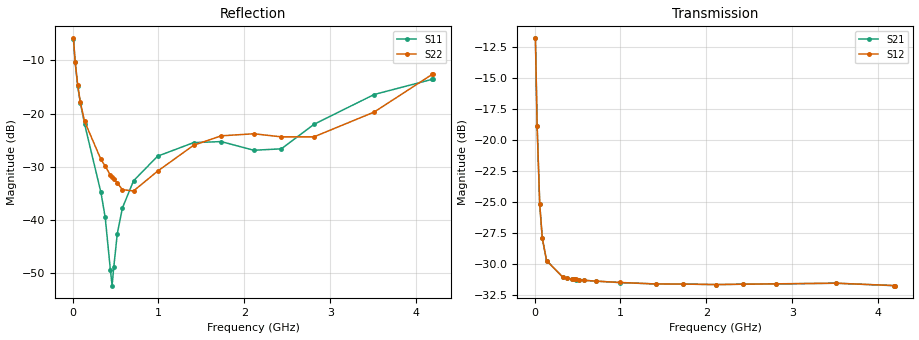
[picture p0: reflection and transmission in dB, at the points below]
! Integrated Device Technology
! Corporate Headquarters
! 6024 Silver Creek Valley Road
! San Jose, CA 95138  USA
! Phone:  1-408-284-8200
! Toll Free:  1-800-223-1366
! Webpage:  http://www.idt.com/
! Timing and RF Division
! 515 Groton Road, Suite 102
! Westford, MA 01886-6024
! Device:  F1950
! Description: 7-bit 0.25 dB Digital Step Attenuator
! Frequency:  150.0 -  4000.00 MHz
! Package:  4x4 mm Thin QFN Plastic Package: 24 pin
! Ports:  2 RF, 12 DC
!  Pin  1  = D0
!  Pin  2  = VDD
!  Pin  3  = Vmode
!  Pin  4  = GND
!  Pin  5  = RF1  =  Port 1
!  Pin  6  = GND
!  Pin  7  = GND
!  Pin  8  = GND
!  Pin  9  = GND
!  Pin 10  = GND
!  Pin 11  = GND
!  Pin 12  = GND
!  Pin 13  = GND
!  Pin 14  = RF2  =  Port 2
!  Pin 15  = GND
!  Pin 16  = LE
!  Pin 17  = CLK
!  Pin 18  = DATE
!  Pin 19  = D6
!  Pin 20  = D5
!  Pin 21  = D4
!  Pin 22  = D3
!  Pin 23  = D2
!  Pin 24  = D1
! State:  122
! Atten State:  30.50 dB
! Voltage:  +5.00 Volts
! Current:  Not Measured mA
! Data:  The device was measured on a the F195X evaluation board which has
!  individual transmission lines to the RF pins.  Data was collected
!  using a calibrated network analyzer.  The evaluation board was
!  de-embedded using a TRL calibration technique.
!  The reference plane is the edge of the package pin.
! Misc:  Board 2019
!  Action Tracker AT0250
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# GHz S dB R 50
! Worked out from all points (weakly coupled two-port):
!   420 points, 10 MHz to 4.2 GHz, reference 50 ohm
!   highest |S21| = -11.82 dB at 10 MHz (marker M1); lowest = -31.7 dB at 4.19 GHz (marker M2)
!   lowest |S11| = -52.3 dB at 460 MHz (marker M3), VSWR 1.00, Z = 49.8 - j0.0964 ohm
!   |S11| at or under -10 dB: 28.27 MHz to end of sweep
!   |S22| runs from -34.8 to -5.8 dB; largest |S21 - S12| = 7.3e-05
!   S11 on the Smith chart (normalised r, x): 10 MHz: 2.04, -1.27; 30 MHz: 1.26, -0.67; 60 MHz: 1.10, -0.37; 330 MHz: 1.01, -0.04; 4.2 GHz: 0.68, +0.17
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0.01  -6.05 -27.9  -11.82 -40.2  -11.82 -40.2  -5.85 -29.0
0.03  -10.35 -52.1  -18.91 -65.9  -18.91 -65.9  -10.21 -53.9
0.06  -14.87 -64.7  -25.18 -60.9  -25.17 -61.0  -14.61 -66.4
0.09  -17.92 -70.3  -27.92 -49.8  -27.92 -49.8  -17.84 -70.8
0.14  -21.96 -73.1  -29.73 -36.6  -29.73 -36.6  -21.46 -75.3
0.33  -34.79 -74.1  -31.07 -19.1  -31.07 -19.1  -28.59 -85.9
0.38  -39.50 -75.5  -31.15 -17.4  -31.15 -17.4  -29.85 -88.2
0.44  -49.33 -108.9  -31.22 -16.0  -31.22 -16.0  -31.53 -94.0
0.46  -52.31 -156.5  -31.24 -15.6  -31.24 -15.6  -31.93 -97.4
0.48  -48.78 161.0  -31.26 -15.3  -31.25 -15.3  -32.22 -100.3
0.52  -42.61 144.9  -31.28 -14.7  -31.28 -14.7  -33.00 -103.9
0.58  -37.71 137.8  -31.32 -14.2  -31.32 -14.2  -34.28 -116.5
0.71  -32.60 139.3  -31.38 -13.5  -31.38 -13.5  -34.51 -141.4
0.99  -27.98 147.8  -31.50 -13.4  -31.49 -13.4  -30.79 179.5
1.41  -25.43 162.8  -31.61 -14.4  -31.61 -14.4  -25.92 160.3
1.73  -25.24 167.9  -31.62 -15.4  -31.62 -15.4  -24.16 151.9
2.11  -26.87 157.5  -31.66 -17.7  -31.66 -17.7  -23.77 142.0
2.43  -26.60 126.3  -31.63 -18.8  -31.63 -18.9  -24.35 131.2
2.81  -22.00 105.6  -31.61 -21.3  -31.60 -21.3  -24.35 115.9
3.51  -16.40 117.4  -31.55 -25.2  -31.55 -25.2  -19.70 113.2
4.19  -13.53 145.1  -31.75 -26.4  -31.74 -26.5  -12.58 127.2
4.2  -13.46 145.5  -31.74 -26.4  -31.75 -26.5  -12.46 127.1
